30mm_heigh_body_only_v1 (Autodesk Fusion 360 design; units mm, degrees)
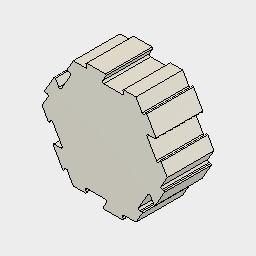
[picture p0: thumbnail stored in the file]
named bodies: "easydetach_30mm"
